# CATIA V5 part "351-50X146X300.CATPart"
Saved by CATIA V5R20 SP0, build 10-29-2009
Part number: 351-50X146X300
Definition: NONE
Nomenclature: 351-50X146X300
Source: Unknown
Description: 351-50X146X300
Bounding box of the stored display mesh (mm): x -10 to 290, y -32.5 to 32.5, z -32.5 to 32.5
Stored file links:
  C:\Users\Utente\Desktop\IO LAVORO\3D X SITO CF\X SITO\PLASTICA\351\351-50X146X300.CATPart

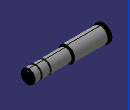
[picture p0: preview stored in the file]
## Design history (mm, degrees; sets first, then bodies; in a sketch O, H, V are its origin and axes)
Body1 "351-50X146X300" (main body)
  Solid1: solid without history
